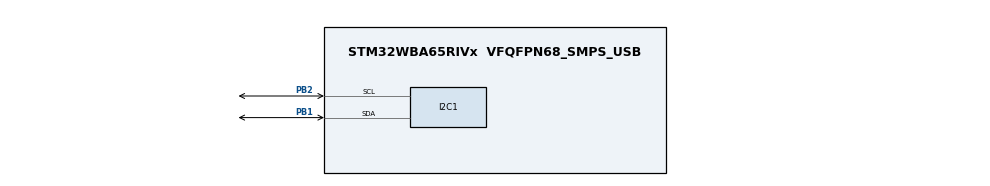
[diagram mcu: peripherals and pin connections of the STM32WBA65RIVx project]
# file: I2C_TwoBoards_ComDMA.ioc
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CORTEX_M33_NS.userName=CORTEX_M33
GPDMA1.LINKALLOCATEDPORT_GPDMACH5=DMA_LINK_ALLOCATED_PORT1
GPDMA1.LINKALLOCATEDPORT_GPDMACH6=DMA_LINK_ALLOCATED_PORT1
GPDMA1.PRIORITY_LL_GPDMACH5=DMA_HIGH_PRIORITY
GPDMA1.PRIORITY_LL_GPDMACH6=DMA_HIGH_PRIORITY
I2C1.AddressingMode=I2C_ADDRESSINGMODE_10BIT
I2C1.OwnAddress=0x5a
I2C1.Timing=0x10C0ECFF
Linkedlist.MDMA_Channel0.GP_SW.0.BlkHWRequest=DMA_BREQ_SINGLE_BURST
Linkedlist.MDMA_Channel0.GP_SW.0.DataHandling=NONE
Linkedlist.MDMA_Channel0.GP_SW.0.DataSize=0
Linkedlist.MDMA_Channel0.GP_SW.0.DestBurstLength=1
Linkedlist.MDMA_Channel0.GP_SW.0.DestDataWidth=DMA_DEST_DATAWIDTH_BYTE
Linkedlist.MDMA_Channel0.GP_SW.0.DestInc=DMA_DINC_FIXED
Linkedlist.MDMA_Channel0.GP_SW.0.Direction=DMA_MEMORY_TO_PERIPH
Linkedlist.MDMA_Channel0.GP_SW.0.DstAddress=0
Linkedlist.MDMA_Channel0.GP_SW.0.Instance=MDMA_Channel0
Linkedlist.MDMA_Channel0.GP_SW.0.LL_MASTERDMA=GPDMA1
Linkedlist.MDMA_Channel0.GP_SW.0.LL_NAME=Queue_tx
Linkedlist.MDMA_Channel0.GP_SW.0.LL_TYPE=LINEAR
Linkedlist.MDMA_Channel0.GP_SW.0.NODE_NAME=Node_tx
Linkedlist.MDMA_Channel0.GP_SW.0.Requestforcodegen=GPDMA1_REQUEST_I2C1_TX
Linkedlist.MDMA_Channel0.GP_SW.0.SrcAddress=0
Linkedlist.MDMA_Channel0.GP_SW.0.SrcBurstLength=1
Linkedlist.MDMA_Channel0.GP_SW.0.SrcDataWidth=DMA_SRC_DATAWIDTH_BYTE
Linkedlist.MDMA_Channel0.GP_SW.0.SrcInc=DMA_SINC_INCREMENTED
Linkedlist.MDMA_Channel0.GP_SW.0.TransferAllocatedPortSrc=DMA_SRC_ALLOCATED_PORT0
Linkedlist.MDMA_Channel0.GP_SW.0.TransferEventMode=DMA_TCEM_BLOCK_TRANSFER
Linkedlist.MDMA_Channel0.GP_SW.0.TriggerPolarity=DMA_TRIG_POLARITY_MASKED
Linkedlist.MDMA_Channel0.Request0=GP_SW
Linkedlist.MDMA_Channel0.RequestsNb=1
Linkedlist.MDMA_Channel1.GP_SW.0.BlkHWRequest=DMA_BREQ_SINGLE_BURST
Linkedlist.MDMA_Channel1.GP_SW.0.DataHandling=NONE
Linkedlist.MDMA_Channel1.GP_SW.0.DataSize=0
Linkedlist.MDMA_Channel1.GP_SW.0.DestBurstLength=1
Linkedlist.MDMA_Channel1.GP_SW.0.DestDataWidth=DMA_DEST_DATAWIDTH_BYTE
Linkedlist.MDMA_Channel1.GP_SW.0.DestInc=DMA_DINC_INCREMENTED
Linkedlist.MDMA_Channel1.GP_SW.0.Direction=DMA_PERIPH_TO_MEMORY
Linkedlist.MDMA_Channel1.GP_SW.0.DstAddress=0
Linkedlist.MDMA_Channel1.GP_SW.0.Instance=MDMA_Channel1
Linkedlist.MDMA_Channel1.GP_SW.0.LL_MASTERDMA=GPDMA1
Linkedlist.MDMA_Channel1.GP_SW.0.LL_NAME=Queue_rx
Linkedlist.MDMA_Channel1.GP_SW.0.LL_TYPE=LINEAR
Linkedlist.MDMA_Channel1.GP_SW.0.NODE_NAME=Node_rx
Linkedlist.MDMA_Channel1.GP_SW.0.Requestforcodegen=GPDMA1_REQUEST_I2C1_RX
Linkedlist.MDMA_Channel1.GP_SW.0.SrcAddress=0
Linkedlist.MDMA_Channel1.GP_SW.0.SrcBurstLength=1
Linkedlist.MDMA_Channel1.GP_SW.0.SrcDataWidth=DMA_SRC_DATAWIDTH_BYTE
Linkedlist.MDMA_Channel1.GP_SW.0.SrcInc=DMA_SINC_FIXED
Linkedlist.MDMA_Channel1.GP_SW.0.TransferAllocatedPortSrc=DMA_SRC_ALLOCATED_PORT0
Linkedlist.MDMA_Channel1.GP_SW.0.TransferEventMode=DMA_TCEM_BLOCK_TRANSFER
Linkedlist.MDMA_Channel1.GP_SW.0.TriggerPolarity=DMA_TRIG_POLARITY_MASKED
Linkedlist.MDMA_Channel1.Request0=GP_SW
Linkedlist.MDMA_Channel1.RequestsNb=1
Linkedlist.RequestSet0=MDMA_Channel0
Linkedlist.RequestSet1=MDMA_Channel1
Linkedlist.RequestSetsNb=2
Mcu.Family=STM32WBA
Mcu.Name=STM32WBA65RIVx
Mcu.Package=VFQFPN68_SMPS_USB
NVIC.GPDMA1_Channel5_IRQn=true\:0\:0\:false\:false\:true\:true\:true\:true
NVIC.GPDMA1_Channel6_IRQn=true\:0\:0\:false\:false\:true\:true\:true\:true
NVIC.I2C1_ER_IRQn=true\:0\:0\:false\:false\:true\:true\:true\:true
NVIC.I2C1_EV_IRQn=true\:0\:0\:false\:false\:true\:true\:true\:true
NVIC.PriorityGroup=NVIC_PRIORITYGROUP_4
OSC_IN.Mode=HSE-External-Oscillator
OSC_IN.PinAttribute=CortexM33
OSC_IN.Signal=RCC_OSC_IN
OSC_OUT.Mode=HSE-External-Oscillator
OSC_OUT.PinAttribute=CortexM33
OSC_OUT.Signal=RCC_OSC_OUT
PB1.GPIO_Pu=GPIO_PULLUP
PB1.GPIO_Speed=GPIO_SPEED_FREQ_HIGH
PB1.Mode=I2C
PB1.PinAttribute=CortexM33
PB1.Signal=I2C1_SDA
PB2.GPIO_Pu=GPIO_PULLUP
PB2.GPIO_Speed=GPIO_SPEED_FREQ_HIGH
PB2.Mode=I2C
PB2.PinAttribute=CortexM33
PB2.Signal=I2C1_SCL
ProjectManager.HeapSize=0x200
ProjectManager.StackSize=0x400
ProjectManager.TargetToolchain=EWARM V9.20
RCC.ADCFreq_Value=100000000
RCC.AHB5CLKDivider=DIV4
RCC.AHBFreq_Value=100000000
RCC.APB1Freq_Value=100000000
RCC.APB1TimFreq_Value=100000000
RCC.APB2Freq_Value=100000000
RCC.APB2TimFreq_Value=100000000
RCC.CortexFreq_Value=12500000
RCC.HCLKFreq_Value=100000000
RCC.HSE_VALUE=32000000
RCC.HSI_VALUE=16000000
RCC.LSE_VALUE=32768
RCC.LSI1_VALUE=32000
RCC.LSI2_VALUE=32000
RCC.PLLFRACN=4096
RCC.PLLM=2
RCC.PLLN=12
RCC.PLLSourceVirtual=RCC_PLLSOURCE_HSE
RCC.SYSCLKFreq_VALUE=100000000
RCC.SYSCLKSourceVirtual=RCC_SYSCLKSOURCE_PLLCLK
RCC.VCOOutputFreq_Value=200000000
VP_CORTEX_M33_NS_VS_Hclk.Mode=Hclk_Mode
VP_GPDMA1_VS_GPDMACH5.Mode=LINKEDLIST_GPDMACH5
VP_GPDMA1_VS_GPDMACH6.Mode=LINKEDLIST_GPDMACH6
VP_ICACHE_VS_ICACHE.Mode=DirectMappedCache
VP_PWR_VS_SECSignals.Mode=Security/Privilege
board=custom

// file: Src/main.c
/* USER CODE BEGIN Header */
/**
  ******************************************************************************
  * @file           : main.c
  * @brief          : Main program body
  ******************************************************************************
  * @attention
  *
  * Copyright (c) 2024 STMicroelectronics.
  * All rights reserved.
  *
  * This software is licensed under terms that can be found in the LICENSE file
  * in the root directory of this software component.
  * If no LICENSE file comes with this software, it is provided AS-IS.
  *
  ******************************************************************************
  */
/* USER CODE END Header */
#include "main.h"

/* USER CODE BEGIN PD */
/* Uncomment this line to use the board as master, if not it is used as slave */
#define MASTER_BOARD

#define I2C_ADDRESS          0x5a
#define BUS_I2Cx_FREQUENCY   100000U

/* Buffer used for transmission */
uint8_t aTxBuffer[] = " ****I2C_TwoBoards communication based on DMA****  ****I2C_TwoBoards communication based on DMA****  ****I2C_TwoBoards communication based on DMA**** ";

/* Buffer used for reception */
uint8_t aRxBuffer[RXBUFFERSIZE];
__IO uint8_t    ubUserButtonClickEvent = RESET;  /* Event detection: Set after User Button interrupt */
/* USER CODE END PD */

DMA_HandleTypeDef handle_GPDMA1_Channel6;
DMA_HandleTypeDef handle_GPDMA1_Channel5;

I2C_HandleTypeDef hi2c1;

void SystemClock_Config(void);
static void MX_GPDMA1_Init(void);
static void MX_GPIO_Init(void);
static void MX_I2C1_Init(void);
static void MX_ICACHE_Init(void);
/* USER CODE BEGIN PFP */
static uint16_t Buffercmp(uint8_t* pBuffer1, uint8_t* pBuffer2, uint16_t BufferLength);
/* USER CODE END PFP */

int main(void)
{

  /* USER CODE BEGIN 1 */
  /* STM32WBAxx HAL library initialization:
       - Systick timer is configured by default as source of time base, but user
             can eventually implement his proper time base source (a general purpose
             timer for example or other time source), keeping in mind that Time base
             duration should be kept 1ms since PPP_TIMEOUT_VALUEs are defined and
             handled in milliseconds basis.
       - Set NVIC Group Priority to 4
       - Low Level Initialization
     */
  /* USER CODE END 1 */

  /* MCU Configuration--------------------------------------------------------*/

  /* Reset of all peripherals, Initializes the Flash interface and the Systick. */
  HAL_Init();

  /* Configure the system clock */
  SystemClock_Config();

  /* USER CODE BEGIN SysInit */
  /* Configure LD1, LD2 and LD3 */
  BSP_LED_Init(LD1);
  BSP_LED_Init(LD2);
  BSP_LED_Init(LD3);
  /* USER CODE END SysInit */

  /* Initialize all configured peripherals */
  MX_GPDMA1_Init();
  MX_GPIO_Init();
  MX_I2C1_Init();
  MX_ICACHE_Init();
  /* USER CODE BEGIN 2 */
  MX_Queue_tx_Config();
  HAL_DMAEx_List_LinkQ(&handle_GPDMA1_Channel6, &Queue_tx);
  __HAL_LINKDMA(&hi2c1, hdmatx, handle_GPDMA1_Channel6);
  MX_Queue_rx_Config();
  HAL_DMAEx_List_LinkQ(&handle_GPDMA1_Channel5, &Queue_rx);
  __HAL_LINKDMA(&hi2c1, hdmarx, handle_GPDMA1_Channel5);

#ifdef MASTER_BOARD

  /* Configure User push-button */
  BSP_PB_Init(B1, BUTTON_MODE_EXTI);

  /* Wait for event on push button to perform following actions */
  while ((ubUserButtonClickEvent) == RESET)
  {
    BSP_LED_Toggle(LD2);
    HAL_Delay(100);
  }
  BSP_LED_Off(LD2);

  /* Delay to avoid that possible signal rebound is taken as button release */
  HAL_Delay(50);

  /* Wait for User push-button release before starting the Communication */
  while (BSP_PB_GetState(B1) != GPIO_PIN_RESET)
  {
  }

  /* The board sends the message and expects to receive it back */

  /*##-2- Start the transmission process #####################################*/
  /* While the I2C in reception process, user can transmit data through
     "aTxBuffer" buffer */
  do
  {
    if(HAL_I2C_Master_Transmit_DMA(&hi2c1, (uint16_t)I2C_ADDRESS, (uint8_t*)aTxBuffer, TXBUFFERSIZE)!= HAL_OK)
    {
      /* Error_Handler() function is called when error occurs. */
      Error_Handler();
    }

    /*##-3- Wait for the end of the transfer #################################*/
    /*  Before starting a new communication transfer, you need to check the current
        state of the peripheral; if it is busy you need to wait for the end of current
        transfer before starting a new one.
        For simplicity reasons, this example is just waiting till the end of the
        transfer, but application may perform other tasks while transfer operation
        is ongoing. */
    while (HAL_I2C_GetState(&hi2c1) != HAL_I2C_STATE_READY)
    {
    }

    /* When Acknowledge failure occurs (Slave don't acknowledge it is address)
       Master restarts communication */
  }
  while(HAL_I2C_GetError(&hi2c1) == HAL_I2C_ERROR_AF);

  /* Turn LD1 on: Transfer in Transmission process is correct */
  BSP_LED_On(LD1);

  /* Wait for User push-button press before starting the Communication */
  while (BSP_PB_GetState(B1) != GPIO_PIN_SET)
  {
    BSP_LED_Toggle(LD2);
    HAL_Delay(100);
  }
  BSP_LED_Off(LD2);

  /* Delay to avoid that possible signal rebound is taken as button release */
  HAL_Delay(50);

  /* Wait for User push-button release before starting the Communication */
  while (BSP_PB_GetState(B1) != GPIO_PIN_RESET)
  {
  }

 /*##-4- Put I2C peripheral in reception process ###########################*/
  do
  {
    if(HAL_I2C_Master_Receive_DMA(&hi2c1, (uint16_t)I2C_ADDRESS, (uint8_t *)aRxBuffer, RXBUFFERSIZE) != HAL_OK)
    {
      /* Error_Handler() function is called when error occurs. */
      Error_Handler();
    }

    /*##-5- Wait for the end of the transfer #################################*/
    /*  Before starting a new communication transfer, you need to check the current
        state of the peripheral; if it is busy you need to wait for the end of current
        transfer before starting a new one.
        For simplicity reasons, this example is just waiting till the end of the
        transfer, but application may perform other tasks while transfer operation
        is ongoing. */
    while (HAL_I2C_GetState(&hi2c1) != HAL_I2C_STATE_READY)
    {
    }

    /* When Acknowledge failure occurs (Slave don't acknowledge it is address)
       Master restarts communication */
  }
  while(HAL_I2C_GetError(&hi2c1) == HAL_I2C_ERROR_AF);

  /* Turn LD1 off: Transfer in reception process is correct */
  BSP_LED_Off(LD1);

#else

  /* The board receives the message and sends it back */

  /*##-2- Put I2C peripheral in reception process ###########################*/
  if(HAL_I2C_Slave_Receive_DMA(&hi2c1, (uint8_t *)aRxBuffer, RXBUFFERSIZE) != HAL_OK)
  {
    /* Transfer error in reception process */
    Error_Handler();
  }

  /*##-3- Wait for the end of the transfer ###################################*/
  /*  Before starting a new communication transfer, you need to check the current
      state of the peripheral; if it is busy you need to wait for the end of current
      transfer before starting a new one.
      For simplicity reasons, this example is just waiting till the end of the
      transfer, but application may perform other tasks while transfer operation
      is ongoing. */
  while (HAL_I2C_GetState(&hi2c1) != HAL_I2C_STATE_READY)
  {
  }

  /* Turn LD1 on: Transfer in reception process is correct */
  BSP_LED_On(LD1);

  /*##-4- Start the transmission process #####################################*/
  /* While the I2C in reception process, user can transmit data through
     "aTxBuffer" buffer */
  if(HAL_I2C_Slave_Transmit_DMA(&hi2c1, (uint8_t*)aTxBuffer, TXBUFFERSIZE)!= HAL_OK)
  {
    /* Transfer error in transmission process */
    Error_Handler();
  }

  /*##-5- Wait for the end of the transfer ###################################*/
  /*  Before starting a new communication transfer, you need to check the current
      state of the peripheral; if it is busy you need to wait for the end of current
      transfer before starting a new one.
      For simplicity reasons, this example is just waiting till the end of the
      transfer, but application may perform other tasks while transfer operation
      is ongoing. */
  while (HAL_I2C_GetState(&hi2c1) != HAL_I2C_STATE_READY)
  {
  }

  /* Turn LD1 off: Transfer in transmission process is correct */
  BSP_LED_Off(LD1);

#endif /* MASTER_BOARD */

  /*##-6- Compare the sent and received buffers ##############################*/
  if(Buffercmp((uint8_t*)aTxBuffer,(uint8_t*)aRxBuffer,RXBUFFERSIZE))
  {
    /* Processing Error */
    Error_Handler();
  }

  /* USER CODE END 2 */

  /* Infinite loop */
  while (1)
  {

  }
}

void SystemClock_Config(void)
{
  RCC_OscInitTypeDef RCC_OscInitStruct = {0};
  RCC_ClkInitTypeDef RCC_ClkInitStruct = {0};

  /** Supply configuration update enable
  */
  HAL_PWREx_ConfigSupply(PWR_LDO_SUPPLY);

  /** Configure the main internal regulator output voltage
  */
  if (HAL_PWREx_ControlVoltageScaling(PWR_REGULATOR_VOLTAGE_SCALE1) != HAL_OK)
  {
    Error_Handler();
  }

  /** Initializes the CPU, AHB and APB busses clocks
  */
  RCC_OscInitStruct.OscillatorType = RCC_OSCILLATORTYPE_HSE;
  RCC_OscInitStruct.HSEState = RCC_HSE_ON;
  RCC_OscInitStruct.HSEDiv = RCC_HSE_DIV1;
  RCC_OscInitStruct.PLL1.PLLState = RCC_PLL_ON;
  RCC_OscInitStruct.PLL1.PLLSource = RCC_PLLSOURCE_HSE;
  RCC_OscInitStruct.PLL1.PLLM = 2;
  RCC_OscInitStruct.PLL1.PLLN = 12;
  RCC_OscInitStruct.PLL1.PLLP = 2;
  RCC_OscInitStruct.PLL1.PLLQ = 2;
  RCC_OscInitStruct.PLL1.PLLR = 2;
  RCC_OscInitStruct.PLL1.PLLFractional = 4096;
  if (HAL_RCC_OscConfig(&RCC_OscInitStruct) != HAL_OK)
  {
    Error_Handler();
  }

  /** Initializes the CPU, AHB and APB busses clocks
  */
  RCC_ClkInitStruct.ClockType = RCC_CLOCKTYPE_HCLK|RCC_CLOCKTYPE_SYSCLK
                              |RCC_CLOCKTYPE_PCLK1|RCC_CLOCKTYPE_PCLK2
                              |RCC_CLOCKTYPE_PCLK7|RCC_CLOCKTYPE_HCLK5;
  RCC_ClkInitStruct.SYSCLKSource = RCC_SYSCLKSOURCE_PLLCLK;
  RCC_ClkInitStruct.AHBCLKDivider = RCC_SYSCLK_DIV1;
  RCC_ClkInitStruct.APB1CLKDivider = RCC_HCLK_DIV1;
  RCC_ClkInitStruct.APB2CLKDivider = RCC_HCLK_DIV1;
  RCC_ClkInitStruct.APB7CLKDivider = RCC_HCLK_DIV1;
  RCC_ClkInitStruct.AHB5_PLL1_CLKDivider = RCC_SYSCLK_PLL1_DIV4;
  RCC_ClkInitStruct.AHB5_HSEHSI_CLKDivider = RCC_SYSCLK_HSEHSI_DIV1;

  if (HAL_RCC_ClockConfig(&RCC_ClkInitStruct, FLASH_LATENCY_3) != HAL_OK)
  {
    Error_Handler();
  }
}

static void MX_GPDMA1_Init(void)
{

  /* Peripheral clock enable */
  __HAL_RCC_GPDMA1_CLK_ENABLE();

  /* GPDMA1 interrupt Init */
    HAL_NVIC_SetPriority(GPDMA1_Channel5_IRQn, 0, 0);
    HAL_NVIC_EnableIRQ(GPDMA1_Channel5_IRQn);
    HAL_NVIC_SetPriority(GPDMA1_Channel6_IRQn, 0, 0);
    HAL_NVIC_EnableIRQ(GPDMA1_Channel6_IRQn);

  handle_GPDMA1_Channel6.Instance = GPDMA1_Channel6;
  handle_GPDMA1_Channel6.InitLinkedList.Priority = DMA_HIGH_PRIORITY;
  handle_GPDMA1_Channel6.InitLinkedList.LinkStepMode = DMA_LSM_FULL_EXECUTION;
  handle_GPDMA1_Channel6.InitLinkedList.LinkAllocatedPort = DMA_LINK_ALLOCATED_PORT1;
  handle_GPDMA1_Channel6.InitLinkedList.TransferEventMode = DMA_TCEM_LAST_LL_ITEM_TRANSFER;
  handle_GPDMA1_Channel6.InitLinkedList.LinkedListMode = DMA_LINKEDLIST_NORMAL;
  if (HAL_DMAEx_List_Init(&handle_GPDMA1_Channel6) != HAL_OK)
  {
    Error_Handler();
  }
  if (HAL_DMA_ConfigChannelAttributes(&handle_GPDMA1_Channel6, DMA_CHANNEL_NPRIV) != HAL_OK)
  {
    Error_Handler();
  }
  handle_GPDMA1_Channel5.Instance = GPDMA1_Channel5;
  handle_GPDMA1_Channel5.InitLinkedList.Priority = DMA_HIGH_PRIORITY;
  handle_GPDMA1_Channel5.InitLinkedList.LinkStepMode = DMA_LSM_FULL_EXECUTION;
  handle_GPDMA1_Channel5.InitLinkedList.LinkAllocatedPort = DMA_LINK_ALLOCATED_PORT1;
  handle_GPDMA1_Channel5.InitLinkedList.TransferEventMode = DMA_TCEM_LAST_LL_ITEM_TRANSFER;
  handle_GPDMA1_Channel5.InitLinkedList.LinkedListMode = DMA_LINKEDLIST_NORMAL;
  if (HAL_DMAEx_List_Init(&handle_GPDMA1_Channel5) != HAL_OK)
  {
    Error_Handler();
  }
  if (HAL_DMA_ConfigChannelAttributes(&handle_GPDMA1_Channel5, DMA_CHANNEL_NPRIV) != HAL_OK)
  {
    Error_Handler();
  }

}

static void MX_I2C1_Init(void)
{

  hi2c1.Instance = I2C1;
  hi2c1.Init.Timing = 0x10C0ECFF;
  hi2c1.Init.OwnAddress1 = 0x5a;
  hi2c1.Init.AddressingMode = I2C_ADDRESSINGMODE_10BIT;
  hi2c1.Init.DualAddressMode = I2C_DUALADDRESS_DISABLE;
  hi2c1.Init.OwnAddress2 = 0;
  hi2c1.Init.OwnAddress2Masks = I2C_OA2_NOMASK;
  hi2c1.Init.GeneralCallMode = I2C_GENERALCALL_DISABLE;
  hi2c1.Init.NoStretchMode = I2C_NOSTRETCH_DISABLE;
  if (HAL_I2C_Init(&hi2c1) != HAL_OK)
  {
    Error_Handler();
  }

  /** Configure Analogue filter
  */
  if (HAL_I2CEx_ConfigAnalogFilter(&hi2c1, I2C_ANALOGFILTER_ENABLE) != HAL_OK)
  {
    Error_Handler();
  }

  /** Configure Digital filter
  */
  if (HAL_I2CEx_ConfigDigitalFilter(&hi2c1, 0) != HAL_OK)
  {
    Error_Handler();
  }

}

static void MX_ICACHE_Init(void)
{

  /** Enable instruction cache in 1-way (direct mapped cache)
  */
  if (HAL_ICACHE_ConfigAssociativityMode(ICACHE_1WAY) != HAL_OK)
  {
    Error_Handler();
  }
  if (HAL_ICACHE_Enable() != HAL_OK)
  {
    Error_Handler();
  }

}

static void MX_GPIO_Init(void)
{

  /* GPIO Ports Clock Enable */
  __HAL_RCC_GPIOB_CLK_ENABLE();

}

/* USER CODE BEGIN 4 */
/**
  * @brief  Tx Transfer completed callback.
  * @param  I2cHandle: I2C handle.
  * @note   This example shows a simple way to report end of DMA Tx transfer, and
  *         you can add your own implementation.
  * @retval None
  */
#ifdef MASTER_BOARD
void HAL_I2C_MasterTxCpltCallback(I2C_HandleTypeDef *I2cHandle)
{
  /* Toggle LD1: Transfer in transmission process is correct */
  BSP_LED_Toggle(LD1);
}
#else
void HAL_I2C_SlaveTxCpltCallback(I2C_HandleTypeDef *I2cHandle)
{
  /* Toggle LD1: Transfer in transmission process is correct */
  BSP_LED_Toggle(LD1);
}
#endif /* MASTER_BOARD */

/**
  * @brief  Rx Transfer completed callback.
  * @param  I2cHandle: I2C handle
  * @note   This example shows a simple way to report end of DMA Rx transfer, and
  *         you can add your own implementation.
  * @retval None
  */
#ifdef MASTER_BOARD
void HAL_I2C_MasterRxCpltCallback(I2C_HandleTypeDef *I2cHandle)
{
  /* Toggle LD1: Transfer in reception process is correct */
  BSP_LED_Toggle(LD1);
}
#else
void HAL_I2C_SlaveRxCpltCallback(I2C_HandleTypeDef *I2cHandle)
{
  /* Toggle LD1: Transfer in reception process is correct */
  BSP_LED_Toggle(LD1);
}
#endif /* MASTER_BOARD */

/**
  * @brief  I2C error callbacks.
  * @param  I2cHandle: I2C handle
  * @note   This example shows a simple way to report transfer error, and you can
  *         add your own implementation.
  * @retval None
  */
void HAL_I2C_ErrorCallback(I2C_HandleTypeDef *I2cHandle)
{
  /** Error_Handler() function is called when error occurs.
    * 1- When Slave doesn't acknowledge its address, Master restarts communication.
    * 2- When Master doesn't acknowledge the last data transferred, Slave doesn't care in this example.
    */
  if (HAL_I2C_GetError(I2cHandle) != HAL_I2C_ERROR_AF)
  {
    /* Turn Off LD1 */
    BSP_LED_Off(LD1);

    /* Turn On LD3 */
    BSP_LED_On(LD3);
  }
}

/**
  * @brief  Compares two buffers.
  * @param  pBuffer1, pBuffer2: buffers to be compared.
  * @param  BufferLength: buffer's length
  * @retval 0  : pBuffer1 identical to pBuffer2
  *         >0 : pBuffer1 differs from pBuffer2
  */
static uint16_t Buffercmp(uint8_t* pBuffer1, uint8_t* pBuffer2, uint16_t BufferLength)
{
  while (BufferLength--)
  {
    if ((*pBuffer1) != *pBuffer2)
    {
      return BufferLength;
    }
    pBuffer1++;
    pBuffer2++;
  }

  return 0;
}

/**
  * @brief EXTI line detection callbacks
  * @param  GPIO_Pin Specifies the port pin connected to corresponding EXTI line.
  * @retval None
  */
void HAL_GPIO_EXTI_Falling_Callback(uint16_t GPIO_Pin)
{
  if (GPIO_Pin == B1_PIN)
  {
    /* Set variable to report push button event to main program */
    ubUserButtonClickEvent = SET;
  }
}
/* USER CODE END 4 */

void Error_Handler(void)
{
  /* USER CODE BEGIN Error_Handler_Debug */
  /* User can add his own implementation to report the HAL error return state */
  __disable_irq();
  /* Turn LD1 off */
  BSP_LED_Off(LD1);
  /* Turn LD3 on */
  BSP_LED_On(LD3);
  while (1)
  {
  }
  /* USER CODE END Error_Handler_Debug */
}
